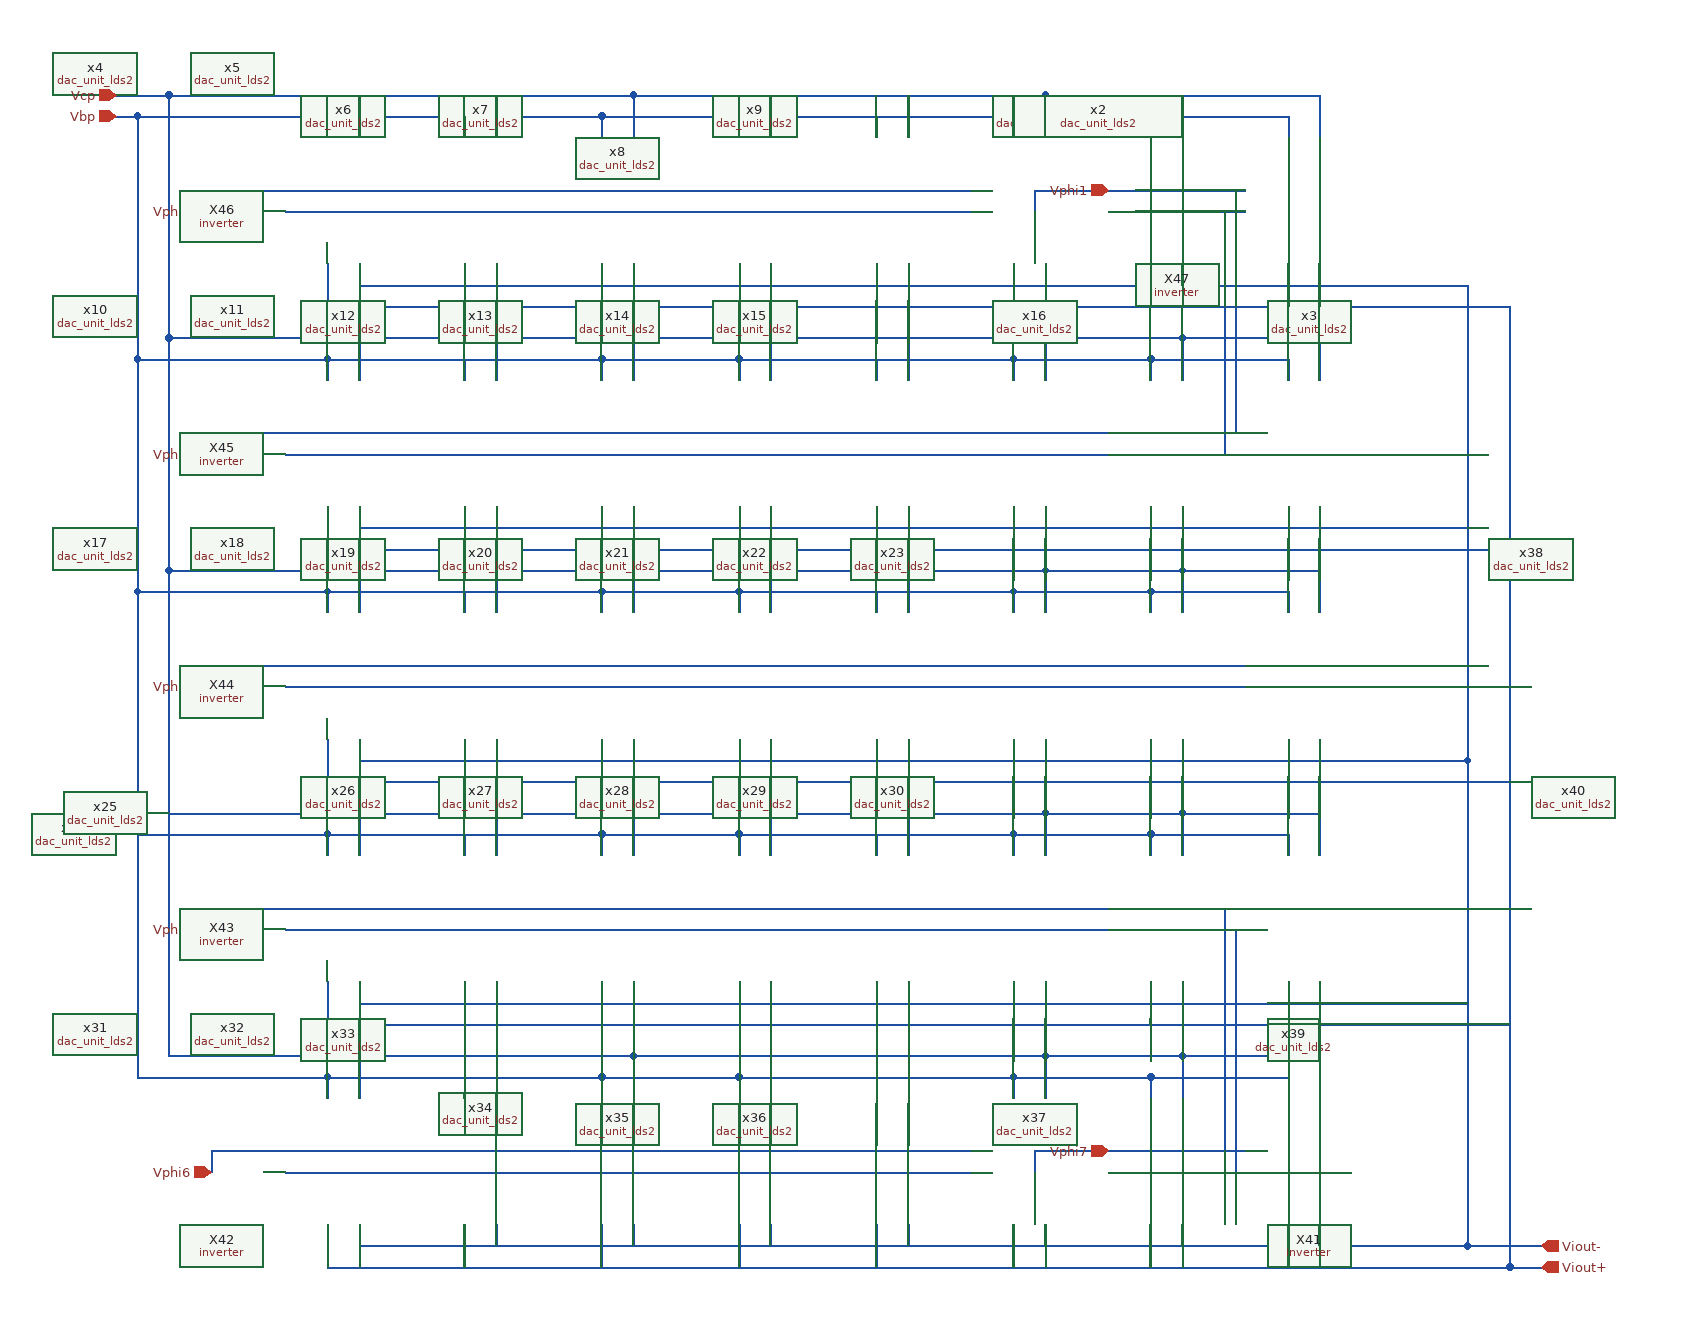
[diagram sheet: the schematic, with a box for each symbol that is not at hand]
v {xschem version=3.4.3 file_version=1.2
}
G {}
K {}
V {}
S {}
E {}
N 1080 270 1080 290 {
lab=Vbp}
N 1210 500 1210 520 {
lab=Vbp}
N 1210 270 1210 290 {
lab=Vbp}
N 1030 270 1080 270 {
lab=Vbp}
N 1240 480 1240 520 {
lab=Vcp}
N 1240 250 1240 290 {
lab=Vcp}
N 1110 250 1110 290 {
lab=Vcp}
N 1040 340 1170 340 {
lab=Vphi1}
N 1040 360 1170 360 {
lab=#net1}
N 300 270 300 290 {
lab=Vbp}
N 300 270 560 270 {
lab=Vbp}
N 560 270 560 290 {
lab=Vbp}
N 430 270 430 290 {
lab=Vbp}
N 250 270 300 270 {
lab=Vbp}
N 250 250 590 250 {
lab=Vcp}
N 590 250 590 290 {
lab=Vcp}
N 460 250 460 290 {
lab=Vcp}
N 330 250 330 290 {
lab=Vcp}
N 150 250 250 250 {
lab=Vcp}
N 120 270 250 270 {
lab=Vbp}
N 690 270 690 290 {
lab=Vbp}
N 690 270 950 270 {
lab=Vbp}
N 950 270 950 290 {
lab=Vbp}
N 820 270 820 290 {
lab=Vbp}
N 640 270 690 270 {
lab=Vbp}
N 640 250 980 250 {
lab=Vcp}
N 980 250 980 290 {
lab=Vcp}
N 850 250 850 290 {
lab=Vcp}
N 720 250 720 290 {
lab=Vcp}
N 590 250 640 250 {
lab=Vcp}
N 560 270 640 270 {
lab=Vbp}
N 260 340 390 340 {
lab=Vphi2}
N 390 340 520 340 {
lab=Vphi2}
N 520 340 650 340 {
lab=Vphi2}
N 650 340 780 340 {
lab=Vphi2}
N 260 360 390 360 {
lab=#net2}
N 390 360 520 360 {
lab=#net2}
N 520 360 650 360 {
lab=#net2}
N 650 360 780 360 {
lab=#net2}
N 780 360 910 360 {
lab=#net2}
N 780 340 910 340 {
lab=Vphi2}
N 1080 410 1080 450 {
lab=Viout+}
N 1210 410 1210 450 {
lab=Viout+}
N 1210 640 1210 680 {
lab=Viout+}
N 1110 410 1110 430 {
lab=Viout-}
N 1240 410 1240 430 {
lab=Viout-}
N 1240 640 1240 660 {
lab=Viout-}
N 300 410 300 450 {
lab=Viout+}
N 430 410 430 450 {
lab=Viout+}
N 560 410 560 450 {
lab=Viout+}
N 330 410 330 430 {
lab=Viout-}
N 460 410 460 430 {
lab=Viout-}
N 590 410 590 430 {
lab=Viout-}
N 690 410 690 450 {
lab=Viout+}
N 720 410 720 430 {
lab=Viout-}
N 820 410 820 450 {
lab=Viout+}
N 850 410 850 430 {
lab=Viout-}
N 950 410 950 450 {
lab=Viout+}
N 980 410 980 430 {
lab=Viout-}
N 300 500 300 520 {
lab=Vbp}
N 300 500 560 500 {
lab=Vbp}
N 560 500 560 520 {
lab=Vbp}
N 430 500 430 520 {
lab=Vbp}
N 250 500 300 500 {
lab=Vbp}
N 250 480 590 480 {
lab=Vcp}
N 590 480 590 520 {
lab=Vcp}
N 460 480 460 520 {
lab=Vcp}
N 330 480 330 520 {
lab=Vcp}
N 690 500 690 520 {
lab=Vbp}
N 690 500 950 500 {
lab=Vbp}
N 950 500 950 520 {
lab=Vbp}
N 820 500 820 520 {
lab=Vbp}
N 640 500 690 500 {
lab=Vbp}
N 640 480 980 480 {
lab=Vcp}
N 980 480 980 520 {
lab=Vcp}
N 850 480 850 520 {
lab=Vcp}
N 720 480 720 520 {
lab=Vcp}
N 590 480 640 480 {
lab=Vcp}
N 560 500 640 500 {
lab=Vbp}
N 260 570 390 570 {
lab=Vphi3}
N 390 570 520 570 {
lab=Vphi3}
N 520 570 650 570 {
lab=Vphi3}
N 650 570 780 570 {
lab=Vphi3}
N 260 590 390 590 {
lab=#net3}
N 390 590 520 590 {
lab=#net3}
N 520 590 650 590 {
lab=#net3}
N 650 590 780 590 {
lab=#net3}
N 780 590 910 590 {
lab=#net3}
N 780 570 910 570 {
lab=Vphi3}
N 300 640 300 680 {
lab=Viout+}
N 430 640 430 680 {
lab=Viout+}
N 560 640 560 680 {
lab=Viout+}
N 330 640 330 660 {
lab=Viout-}
N 460 640 460 660 {
lab=Viout-}
N 590 640 590 660 {
lab=Viout-}
N 690 640 690 680 {
lab=Viout+}
N 720 640 720 660 {
lab=Viout-}
N 820 640 820 680 {
lab=Viout+}
N 850 640 850 660 {
lab=Viout-}
N 950 640 950 680 {
lab=Viout+}
N 980 640 980 660 {
lab=Viout-}
N 910 570 1040 570 {
lab=Vphi3}
N 910 590 1040 590 {
lab=#net3}
N 980 480 1110 480 {
lab=Vcp}
N 1110 480 1110 520 {
lab=Vcp}
N 950 500 1080 500 {
lab=Vbp}
N 1080 500 1080 520 {
lab=Vbp}
N 1080 640 1080 680 {
lab=Viout+}
N 1110 640 1110 660 {
lab=Viout-}
N 300 720 300 740 {
lab=Vbp}
N 300 720 560 720 {
lab=Vbp}
N 560 720 560 740 {
lab=Vbp}
N 430 720 430 740 {
lab=Vbp}
N 250 720 300 720 {
lab=Vbp}
N 250 700 590 700 {
lab=Vcp}
N 590 700 590 740 {
lab=Vcp}
N 460 700 460 740 {
lab=Vcp}
N 330 700 330 740 {
lab=Vcp}
N 690 720 690 740 {
lab=Vbp}
N 690 720 950 720 {
lab=Vbp}
N 950 720 950 740 {
lab=Vbp}
N 820 720 820 740 {
lab=Vbp}
N 640 720 690 720 {
lab=Vbp}
N 640 700 980 700 {
lab=Vcp}
N 980 700 980 740 {
lab=Vcp}
N 850 700 850 740 {
lab=Vcp}
N 720 700 720 740 {
lab=Vcp}
N 590 700 640 700 {
lab=Vcp}
N 560 720 640 720 {
lab=Vbp}
N 260 790 390 790 {
lab=Vphi4}
N 390 790 520 790 {
lab=Vphi4}
N 520 790 650 790 {
lab=Vphi4}
N 650 790 780 790 {
lab=Vphi4}
N 260 810 390 810 {
lab=#net4}
N 390 810 520 810 {
lab=#net4}
N 520 810 650 810 {
lab=#net4}
N 650 810 780 810 {
lab=#net4}
N 780 810 910 810 {
lab=#net4}
N 780 790 910 790 {
lab=Vphi4}
N 300 860 300 900 {
lab=Viout+}
N 430 860 430 900 {
lab=Viout+}
N 560 860 560 900 {
lab=Viout+}
N 330 860 330 880 {
lab=Viout-}
N 460 860 460 880 {
lab=Viout-}
N 590 860 590 880 {
lab=Viout-}
N 690 860 690 900 {
lab=Viout+}
N 720 860 720 880 {
lab=Viout-}
N 820 860 820 900 {
lab=Viout+}
N 850 860 850 880 {
lab=Viout-}
N 950 860 950 900 {
lab=Viout+}
N 980 860 980 880 {
lab=Viout-}
N 910 790 1040 790 {
lab=Vphi4}
N 910 810 1040 810 {
lab=#net4}
N 980 700 1110 700 {
lab=Vcp}
N 1110 700 1110 740 {
lab=Vcp}
N 950 720 1080 720 {
lab=Vbp}
N 1080 720 1080 740 {
lab=Vbp}
N 1080 860 1080 900 {
lab=Viout+}
N 1110 860 1110 880 {
lab=Viout-}
N 150 250 150 480 {
lab=Vcp}
N 150 480 250 480 {
lab=Vcp}
N 120 270 120 500 {
lab=Vbp}
N 120 500 250 500 {
lab=Vbp}
N 150 480 150 700 {
lab=Vcp}
N 150 700 250 700 {
lab=Vcp}
N 120 500 120 720 {
lab=Vbp}
N 120 720 250 720 {
lab=Vbp}
N 300 950 300 970 {
lab=Vbp}
N 300 950 560 950 {
lab=Vbp}
N 560 950 560 970 {
lab=Vbp}
N 430 950 430 970 {
lab=Vbp}
N 250 950 300 950 {
lab=Vbp}
N 250 930 590 930 {
lab=Vcp}
N 590 930 590 970 {
lab=Vcp}
N 460 930 460 970 {
lab=Vcp}
N 330 930 330 970 {
lab=Vcp}
N 690 950 690 970 {
lab=Vbp}
N 690 950 950 950 {
lab=Vbp}
N 950 950 950 970 {
lab=Vbp}
N 820 950 820 970 {
lab=Vbp}
N 640 950 690 950 {
lab=Vbp}
N 640 930 980 930 {
lab=Vcp}
N 980 930 980 970 {
lab=Vcp}
N 850 930 850 970 {
lab=Vcp}
N 720 930 720 970 {
lab=Vcp}
N 590 930 640 930 {
lab=Vcp}
N 560 950 640 950 {
lab=Vbp}
N 260 1020 390 1020 {
lab=Vphi5}
N 390 1020 520 1020 {
lab=Vphi5}
N 520 1020 650 1020 {
lab=Vphi5}
N 650 1020 780 1020 {
lab=Vphi5}
N 260 1040 390 1040 {
lab=#net5}
N 390 1040 520 1040 {
lab=#net5}
N 520 1040 650 1040 {
lab=#net5}
N 650 1040 780 1040 {
lab=#net5}
N 780 1040 910 1040 {
lab=#net5}
N 780 1020 910 1020 {
lab=Vphi5}
N 300 1090 300 1130 {
lab=Viout+}
N 430 1090 430 1130 {
lab=Viout+}
N 560 1090 560 1130 {
lab=Viout+}
N 330 1090 330 1110 {
lab=Viout-}
N 460 1090 460 1110 {
lab=Viout-}
N 590 1090 590 1110 {
lab=Viout-}
N 690 1090 690 1130 {
lab=Viout+}
N 720 1090 720 1110 {
lab=Viout-}
N 820 1090 820 1130 {
lab=Viout+}
N 850 1090 850 1110 {
lab=Viout-}
N 950 1090 950 1130 {
lab=Viout+}
N 980 1090 980 1110 {
lab=Viout-}
N 910 1020 1040 1020 {
lab=Vphi5}
N 910 1040 1040 1040 {
lab=#net5}
N 980 930 1110 930 {
lab=Vcp}
N 1110 930 1110 970 {
lab=Vcp}
N 950 950 1080 950 {
lab=Vbp}
N 1080 950 1080 970 {
lab=Vbp}
N 1080 1090 1080 1130 {
lab=Viout+}
N 1110 1090 1110 1110 {
lab=Viout-}
N 300 1180 300 1200 {
lab=Vbp}
N 300 1180 560 1180 {
lab=Vbp}
N 560 1180 560 1200 {
lab=Vbp}
N 430 1180 430 1200 {
lab=Vbp}
N 250 1180 300 1180 {
lab=Vbp}
N 250 1160 590 1160 {
lab=Vcp}
N 590 1160 590 1200 {
lab=Vcp}
N 460 1160 460 1200 {
lab=Vcp}
N 330 1160 330 1200 {
lab=Vcp}
N 690 1180 690 1200 {
lab=Vbp}
N 690 1180 950 1180 {
lab=Vbp}
N 950 1180 950 1200 {
lab=Vbp}
N 820 1180 820 1200 {
lab=Vbp}
N 640 1180 690 1180 {
lab=Vbp}
N 640 1160 980 1160 {
lab=Vcp}
N 980 1160 980 1200 {
lab=Vcp}
N 850 1160 850 1200 {
lab=Vcp}
N 720 1160 720 1200 {
lab=Vcp}
N 590 1160 640 1160 {
lab=Vcp}
N 560 1180 640 1180 {
lab=Vbp}
N 260 1250 390 1250 {
lab=Vphi6}
N 390 1250 520 1250 {
lab=Vphi6}
N 520 1250 650 1250 {
lab=Vphi6}
N 650 1250 780 1250 {
lab=Vphi6}
N 260 1270 390 1270 {
lab=#net6}
N 390 1270 520 1270 {
lab=#net6}
N 520 1270 650 1270 {
lab=#net6}
N 650 1270 780 1270 {
lab=#net6}
N 780 1270 910 1270 {
lab=#net6}
N 780 1250 910 1250 {
lab=Vphi6}
N 300 1320 300 1360 {
lab=Viout+}
N 430 1320 430 1360 {
lab=Viout+}
N 560 1320 560 1360 {
lab=Viout+}
N 330 1320 330 1340 {
lab=Viout-}
N 460 1320 460 1340 {
lab=Viout-}
N 590 1320 590 1340 {
lab=Viout-}
N 690 1320 690 1360 {
lab=Viout+}
N 720 1320 720 1340 {
lab=Viout-}
N 820 1320 820 1360 {
lab=Viout+}
N 850 1320 850 1340 {
lab=Viout-}
N 950 1320 950 1360 {
lab=Viout+}
N 980 1320 980 1340 {
lab=Viout-}
N 1210 860 1210 900 {
lab=Viout+}
N 1240 860 1240 880 {
lab=Viout-}
N 330 880 1380 880 {
lab=Viout-}
N 300 900 1420 900 {
lab=Viout+}
N 1040 790 1170 790 {
lab=Vphi4}
N 1040 810 1170 810 {
lab=#net4}
N 1110 700 1240 700 {
lab=Vcp}
N 1240 700 1240 740 {
lab=Vcp}
N 1210 720 1210 740 {
lab=Vbp}
N 1080 720 1210 720 {
lab=Vbp}
N 330 660 1380 660 {
lab=Viout-}
N 300 680 1420 680 {
lab=Viout+}
N 330 1110 1380 1110 {
lab=Viout-}
N 300 1130 1420 1130 {
lab=Viout+}
N 330 1340 1380 1340 {
lab=Viout-}
N 300 1360 1420 1360 {
lab=Viout+}
N 1080 1180 1080 1200 {
lab=Vbp}
N 1210 950 1210 970 {
lab=Vbp}
N 1210 1180 1210 1200 {
lab=Vbp}
N 1030 1180 1080 1180 {
lab=Vbp}
N 1240 930 1240 970 {
lab=Vcp}
N 1240 1160 1240 1200 {
lab=Vcp}
N 1110 1160 1110 1200 {
lab=Vcp}
N 1040 1250 1170 1250 {
lab=Vphi7}
N 1040 1270 1170 1270 {
lab=#net7}
N 1080 1320 1080 1360 {
lab=Viout+}
N 1210 1320 1210 1360 {
lab=Viout+}
N 1210 1090 1210 1130 {
lab=Viout+}
N 1110 1320 1110 1340 {
lab=Viout-}
N 1240 1320 1240 1340 {
lab=Viout-}
N 1240 1090 1240 1110 {
lab=Viout-}
N 150 930 250 930 {
lab=Vcp}
N 120 950 250 950 {
lab=Vbp}
N 150 1160 250 1160 {
lab=Vcp}
N 120 1180 250 1180 {
lab=Vbp}
N 1420 450 1420 680 {
lab=Viout+}
N 330 430 1380 430 {
lab=Viout-}
N 300 450 1420 450 {
lab=Viout+}
N 1380 430 1380 880 {
lab=Viout-}
N 1420 1360 1450 1360 {
lab=Viout+}
N 970 340 970 360 {
lab=Vphi1}
N 970 340 1040 340 {
lab=Vphi1}
N 190 340 190 360 {
lab=Vphi2}
N 190 340 260 340 {
lab=Vphi2}
N 190 570 190 590 {
lab=Vphi3}
N 190 570 260 570 {
lab=Vphi3}
N 190 790 190 810 {
lab=Vphi4}
N 190 790 260 790 {
lab=Vphi4}
N 190 1020 190 1040 {
lab=Vphi5}
N 190 1020 260 1020 {
lab=Vphi5}
N 190 1250 190 1270 {
lab=Vphi6}
N 190 1250 260 1250 {
lab=Vphi6}
N 970 1250 970 1270 {
lab=Vphi7}
N 970 1250 1040 1250 {
lab=Vphi7}
N 1380 1340 1450 1340 {
lab=Viout-}
N 950 270 1030 270 {
lab=Vbp}
N 980 250 1030 250 {
lab=Vcp}
N 100 250 150 250 {
lab=Vcp}
N 100 270 120 270 {
lab=Vbp}
N 1030 250 1240 250 {
lab=Vcp}
N 1080 270 1210 270 {
lab=Vbp}
N 1110 480 1240 480 {
lab=Vcp}
N 1080 500 1210 500 {
lab=Vbp}
N 1160 340 1160 570 {
lab=Vphi1}
N 1160 570 1170 570 {
lab=Vphi1}
N 1150 590 1170 590 {
lab=#net1}
N 1150 360 1150 590 {
lab=#net1}
N 950 1180 1030 1180 {
lab=Vbp}
N 980 1160 1110 1160 {
lab=Vcp}
N 1110 1160 1240 1160 {
lab=Vcp}
N 1080 1180 1210 1180 {
lab=Vbp}
N 1160 1040 1170 1040 {
lab=#net7}
N 1160 1040 1160 1270 {
lab=#net7}
N 1150 1020 1170 1020 {
lab=Vphi7}
N 1150 1020 1150 1250 {
lab=Vphi7}
N 1110 930 1240 930 {
lab=Vcp}
N 1080 950 1210 950 {
lab=Vbp}
N 150 700 150 1160 {
lab=Vcp}
N 120 720 120 1180 {
lab=Vbp}
N 1380 880 1380 1340 {}
N 1420 680 1420 1360 {}
C {./dac_unit_lds2.sym} 860 230 0 0 {name=x1}
C {./dac_unit_lds2.sym} 990 230 0 0 {name=x2}
C {./dac_unit_lds2.sym} 990 460 0 0 {name=x3}
C {./dac_unit_lds2.sym} 80 230 0 0 {name=x4}
C {./dac_unit_lds2.sym} 210 230 0 0 {name=x5}
C {./dac_unit_lds2.sym} 340 230 0 0 {name=x6}
C {./dac_unit_lds2.sym} 470 230 0 0 {name=x7}
C {./dac_unit_lds2.sym} 600 230 0 0 {name=x8}
C {./dac_unit_lds2.sym} 730 230 0 0 {name=x9}
C {./dac_unit_lds2.sym} 80 460 0 0 {name=x10}
C {./dac_unit_lds2.sym} 210 460 0 0 {name=x11}
C {./dac_unit_lds2.sym} 340 460 0 0 {name=x12}
C {./dac_unit_lds2.sym} 470 460 0 0 {name=x13}
C {./dac_unit_lds2.sym} 600 460 0 0 {name=x14}
C {./dac_unit_lds2.sym} 730 460 0 0 {name=x15}
C {./dac_unit_lds2.sym} 860 460 0 0 {name=x16}
C {./dac_unit_lds2.sym} 80 680 0 0 {name=x17}
C {./dac_unit_lds2.sym} 210 680 0 0 {name=x18}
C {./dac_unit_lds2.sym} 340 680 0 0 {name=x19}
C {./dac_unit_lds2.sym} 470 680 0 0 {name=x20}
C {./dac_unit_lds2.sym} 600 680 0 0 {name=x21}
C {./dac_unit_lds2.sym} 730 680 0 0 {name=x22}
C {./dac_unit_lds2.sym} 860 680 0 0 {name=x23}
C {./dac_unit_lds2.sym} 80 910 0 0 {name=x24}
C {./dac_unit_lds2.sym} 210 910 0 0 {name=x25}
C {./dac_unit_lds2.sym} 340 910 0 0 {name=x26}
C {./dac_unit_lds2.sym} 470 910 0 0 {name=x27}
C {./dac_unit_lds2.sym} 600 910 0 0 {name=x28}
C {./dac_unit_lds2.sym} 730 910 0 0 {name=x29}
C {./dac_unit_lds2.sym} 860 910 0 0 {name=x30}
C {./dac_unit_lds2.sym} 80 1140 0 0 {name=x31}
C {./dac_unit_lds2.sym} 210 1140 0 0 {name=x32}
C {./dac_unit_lds2.sym} 340 1140 0 0 {name=x33}
C {./dac_unit_lds2.sym} 470 1140 0 0 {name=x34}
C {./dac_unit_lds2.sym} 600 1140 0 0 {name=x35}
C {./dac_unit_lds2.sym} 730 1140 0 0 {name=x36}
C {./dac_unit_lds2.sym} 990 680 0 0 {name=x38}
C {./dac_unit_lds2.sym} 860 1140 0 0 {name=x37}
C {./dac_unit_lds2.sym} 990 1140 0 0 {name=x39}
C {./dac_unit_lds2.sym} 990 910 0 0 {name=x40}
C {devices/ipin.sym} 1040 340 1 0 {name=p3 lab=Vphi1}
C {devices/ipin.sym} 190 360 0 0 {name=p4 lab=Vphi2}
C {devices/ipin.sym} 190 590 0 0 {name=p5 lab=Vphi3}
C {devices/ipin.sym} 190 810 0 0 {name=p6 lab=Vphi4}
C {devices/ipin.sym} 190 1040 0 0 {name=p7 lab=Vphi5}
C {devices/ipin.sym} 190 1270 0 0 {name=p8 lab=Vphi6}
C {devices/ipin.sym} 1040 1250 1 0 {name=p9 lab=Vphi7}
C {devices/opin.sym} 1450 1360 0 0 {name=p1 lab=Viout+}
C {devices/opin.sym} 1450 1340 0 0 {name=p2 lab=Viout-}
C {devices/ipin.sym} 100 250 0 0 {name=p10 lab=Vcp}
C {devices/ipin.sym} 100 270 0 0 {name=p11 lab=Vbp}
C {/home/madvlsi/VLSI_Sine_Gen/simulation/dac/inverter.sym} 1050 1270 0 0 {name=X41}
C {/home/madvlsi/VLSI_Sine_Gen/simulation/dac/inverter.sym} 270 1270 0 0 {name=X42}
C {/home/madvlsi/VLSI_Sine_Gen/simulation/dac/inverter.sym} 270 1040 0 0 {name=X43}
C {/home/madvlsi/VLSI_Sine_Gen/simulation/dac/inverter.sym} 270 810 0 0 {name=X44}
C {/home/madvlsi/VLSI_Sine_Gen/simulation/dac/inverter.sym} 270 590 0 0 {name=X45}
C {/home/madvlsi/VLSI_Sine_Gen/simulation/dac/inverter.sym} 270 360 0 0 {name=X46}
C {/home/madvlsi/VLSI_Sine_Gen/simulation/dac/inverter.sym} 1050 360 0 0 {name=X47}
